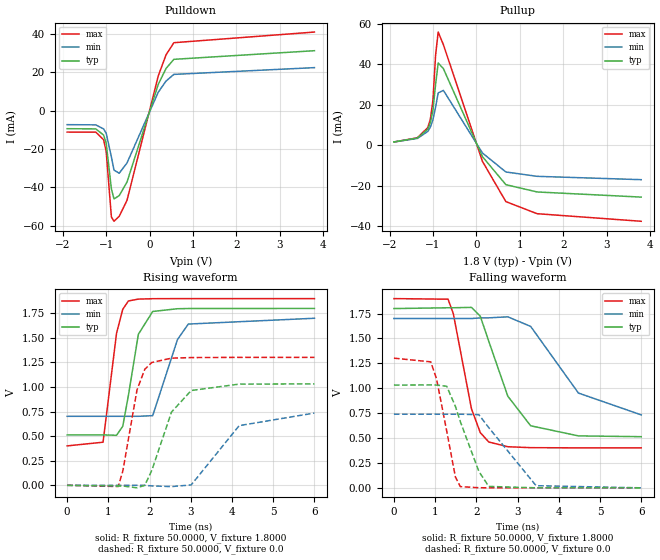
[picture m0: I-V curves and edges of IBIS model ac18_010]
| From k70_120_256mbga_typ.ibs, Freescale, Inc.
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|   Model ac18_010
[Model]  ac18_010
Model_type Output
Polarity   Non-Inverting
Enable   Active-High
Vmeas =  0.9000V
Cref =   5.0000pF
Rref =   50.0000
C_comp   2.8000pF   2.5000pF   3.3000pF
[Temperature Range]   25.0000   0.1250k   -40.0000
[Voltage Range]   1.8000V   1.7000V   1.9000V
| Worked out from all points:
|   slope of the pulldown table from 0 to 0.27 V, typ, clamps not added: 15.7 ohm
|   slope of the pullup table from 0 to 0.27 V, typ, clamps not added: 26.3 ohm
|   rising waveform, R_fixture 50.0000, V_fixture 1.8000: 20-80 % time 297ps typ, 390ps min, 244ps max; typ from 0.513 V to 1.8 V
|   rising waveform, R_fixture 50.0000, V_fixture 0.0: 20-80 % time 553ps typ, 807ps min, 342ps max; typ from 0 V to 1.03 V
|   falling waveform, R_fixture 50.0000, V_fixture 1.8000: 20-80 % time 715ps typ, 1.05ns min, 437ps max; typ from 1.8 V to 0.514 V
|   falling waveform, R_fixture 50.0000, V_fixture 0.0: 20-80 % time 535ps typ, 755ps min, 360ps max; typ from 1.03 V to 0 V
[Pulldown]
|Voltage   I(typ)   I(min)   I(max)
-1.9V     -9.45mA    -7.352mA   -11.21mA
-1.24V    -9.541mA   -7.451mA   -11.23mA
-1.06V    -12.75mA   -9.557mA   -15.18mA
-1V       -16.97mA   -11.82mA   -21.29mA
-880mV    -40.74mA   -24.13mA   -55.33mA
-820mV    -45.95mA   -31mA      -57.58mA
-700mV    -44.25mA   -32.6mA    -54.97mA
-520mV    -37.18mA   -27.26mA   -46.71mA
200mV     13.59mA    9.515mA    17.98mA
380mV     21.87mA    15.33mA    28.97mA
560mV     26.62mA    18.78mA    35.26mA
3.8V      31.1mA     22.3mA     40.8mA
[Pullup]
|Voltage   I(typ)   I(min)   I(max)
-1.9V     1.5mA      1.5mA      1.5mA
-1.36V    3.45mA     3.24mA     3.57mA
-1.12V    7.8mA      6.69mA     8.6mA
-1.06V    10.98mA    8.87mA     12.77mA
-1V       17.34mA    12.56mA    22.4mA
-940mV    29.86mA    18.76mA    44.29mA
-880mV    40.52mA    25.74mA    55.8mA
-760mV    37.72mA    26.99mA    49.56mA
140mV     -5.745mA   -3.949mA   -8.077mA
680mV     -19.58mA   -13.32mA   -27.96mA
1.4V      -23.19mA   -15.47mA   -33.93mA
3.8V      -25.73mA   -17.12mA   -37.67mA
[Ramp]
| variable   typ   min   max
dV/dt_r  0.6195/0.5526n   0.4413/0.8066n   0.7809/0.3418n
dV/dt_f  0.7719/0.7150n   0.5805/1.0484n   0.8992/0.4375n
R_load = 50.0000
[Rising Waveform]
R_fixture= 50.0000
V_fixture= 1.8000
V_fixture_min= 1.7000
V_fixture_max= 1.9000
|time   V(typ)   V(min)   V(max)
0s        513.2mV    702.3mV    401.3mV
871.4ps   513.2mV    702.3mV    438.8mV
1.199ns   509mV      702.3mV    1.548V
1.35ns    601.7mV    702.3mV    1.792V
1.487ns   916.1mV    702.3mV    1.876V
1.728ns   1.537V     702.5mV    1.895V
2.076ns   1.769V     709mV      1.899V
2.677ns   1.797V     1.483V     1.9V
2.94ns    1.799V     1.641V     1.9V
6ns       1.8V       1.7V       1.9V
[Rising Waveform]
R_fixture= 50.0000
V_fixture= 0.0
|time   V(typ)   V(min)   V(max)
0s        3.704nV    400.4nV    961.2pV
1.239ns   -7.034mV   855.3nV    -12.25mV
1.351ns   -6.76mV    491.1nV    145.3mV
1.695ns   -25.53mV   10.75uV    970.7mV
1.884ns   -346.7uV   382.5uV    1.181V
2.055ns   153.4mV    -6.023mV   1.25V
2.532ns   745.5mV    -12.79mV   1.294V
3.01ns    964.7mV    3.984mV    1.3V
4.174ns   1.03V      607.3mV    1.302V
6ns       1.032V     735.5mV    1.302V
[Falling Waveform]
R_fixture= 50.0000
V_fixture= 1.8000
V_fixture_min= 1.7000
V_fixture_max= 1.9000
|time   V(typ)   V(min)   V(max)
0s        1.8V       1.7V       1.9V
1.313ns   1.808V     1.7V       1.894V
1.441ns   1.808V     1.7V       1.748V
1.881ns   1.812V     1.7V       793.8mV
2.095ns   1.723V     1.706V     554.5mV
2.303ns   1.469V     1.707V     459.9mV
2.763ns   920.2mV    1.717V     412.8mV
3.317ns   623.2mV    1.621V     403.3mV
4.476ns   521.5mV    951.7mV    401.4mV
6ns       513.6mV    732.5mV    401.3mV
[Falling Waveform]
R_fixture= 50.0000
V_fixture= 0.0
|time   V(typ)   V(min)   V(max)
0s        1.032V     739.4mV    1.302V
892.8ps   1.033V     739.4mV    1.265V
1.034ns   1.032V     739.4mV    1.094V
1.28ns    1.02V      739.4mV    571.4mV
1.491ns   818.4mV    739.4mV    109.6mV
1.61ns    666.1mV    739.4mV    12.12mV
2.061ns   164.2mV    734.4mV    1.132mV
2.301ns   14.11mV    604.3mV    499.3uV
3.449ns   310.9uV    21.55mV    13.97uV
6ns       1.814uV    71.36uV    118.4nV
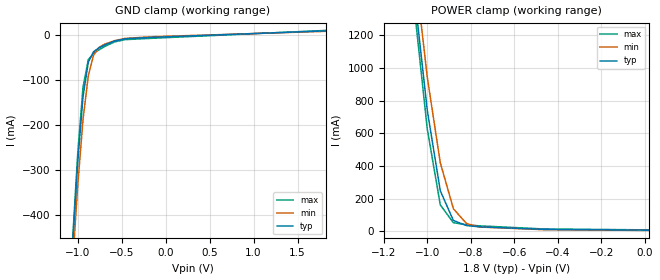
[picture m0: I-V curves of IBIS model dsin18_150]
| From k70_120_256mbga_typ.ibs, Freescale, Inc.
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|   Model dsin18_150
[Model]  dsin18_150
Model_type Input
Polarity   Non-Inverting
Enable   Active-High
Vinl =   0.6500V
Vinh =   1.1500V
C_comp   2.8000pF   2.5000pF   3.3000pF
[Temperature Range]   25.0000   0.1250k   -40.0000
[Voltage Range]   1.8000V   1.7000V   1.9000V
[GND_clamp]
|Voltage   I(typ)   I(min)   I(max)
-1.9V     -3.889A    -3.846A    -3.936A
-1.06V    -471.8mA   -515.1mA   -461.5mA
-1V       -283.2mA   -335mA     -263.8mA
-940mV    -138.2mA   -188.6mA   -116.8mA
-880mV    -61.42mA   -91.58mA   -55.71mA
-820mV    -38.02mA   -45.51mA   -41.82mA
-760mV    -29.59mA   -28.84mA   -34.03mA
-700mV    -23.58mA   -21.7mA    -27.07mA
-580mV    -14.23mA   -13.38mA   -16.04mA
-460mV    -9.258mA   -8.379mA   -11.1mA
-160mV    -6.128mA   -4.733mA   -8.206mA
1.82V     8.347mA    7.356mA    9.323mA
[POWER_clamp]
|Voltage   I(typ)   I(min)   I(max)
-1.9V     15A        14.9A      15.11A
-1.06V    1.464A     1.643A     1.375A
-1V       741.7mA    944.2mA    627.2mA
-940mV    248.2mA    419.2mA    162.4mA
-880mV    67.86mA    139.2mA    53.9mA
-820mV    36.11mA    49.11mA    40.83mA
-760mV    28.51mA    27.31mA    34.47mA
-460mV    12.75mA    10.85mA    15.2mA
20mV      8.034mA    6.463mA    9.888mA
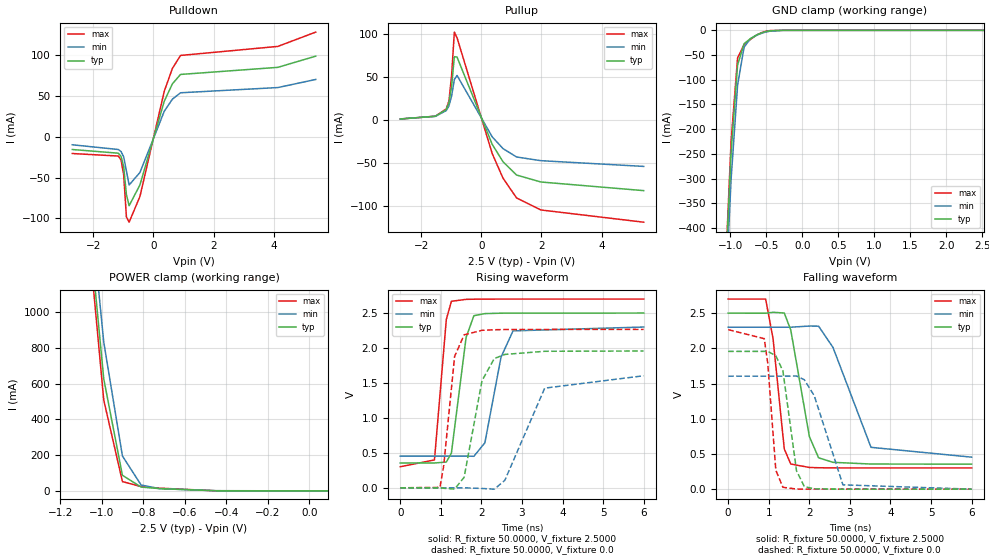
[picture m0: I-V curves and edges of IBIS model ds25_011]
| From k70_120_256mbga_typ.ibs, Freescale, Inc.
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|   Model ds25_011
[Model]  ds25_011
Model_type 3-state
Polarity   Non-Inverting
Enable   Active-High
Vmeas =  1.2500V
Cref =   5.0000pF
Rref =   50.0000
C_comp   2.8000pF   2.5000pF   3.3000pF
[Temperature Range]   25.0000   0.1250k   -40.0000
[Voltage Range]   2.5000V   2.3000V   2.7000V
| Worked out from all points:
|   slope of the pulldown table from 0 to 0.375 V, typ, clamps not added: 8.39 ohm
|   slope of the pullup table from 0 to 0.375 V, typ, clamps not added: 13 ohm
|   GND clamp passes 1 mA (typ) near -0.45 V on its own axis
|   POWER clamp passes 1 mA (typ) near -0.45 V on its own axis
|   rising waveform, R_fixture 50.0000, V_fixture 2.5000: 20-80 % time 258ps typ, 355ps min, 178ps max; typ from 0.355 V to 2.5 V
|   rising waveform, R_fixture 50.0000, V_fixture 0.0: 20-80 % time 370ps typ, 632ps min, 227ps max; typ from 0 V to 1.96 V
|   falling waveform, R_fixture 50.0000, V_fixture 2.5000: 20-80 % time 366ps typ, 605ps min, 248ps max; typ from 2.5 V to 0.355 V
|   falling waveform, R_fixture 50.0000, V_fixture 0.0: 20-80 % time 260ps typ, 438ps min, 172ps max; typ from 1.96 V to 0 V
[Pulldown]
|Voltage   I(typ)   I(min)   I(max)
-2.7V     -15.75mA   -9.975mA   -20.66mA
-1.17V    -20.25mA   -15.73mA   -23.74mA
-1.08V    -24.05mA   -18.2mA    -28.35mA
-990mV    -36.68mA   -24.84mA   -46.96mA
-900mV    -71.11mA   -42.05mA   -98.2mA
-810mV    -84.45mA   -59.11mA   -104.6mA
-450mV    -59.03mA   -43.84mA   -73.17mA
360mV     43.36mA    31.02mA    55.53mA
630mV     64.54mA    45.79mA    83.38mA
900mV     76.02mA    53.6mA     99.25mA
4.14V     84.7mA     60mA       110.3mA
5.4V      98.4mA     69.9mA     127.8mA
[Pullup]
|Voltage   I(typ)   I(min)   I(max)
-2.7V     1.5mA      1.6mA      1.5mA
-1.53V    4.72mA     4.58mA     4.76mA
-1.17V    12.5mA     11.26mA    13.19mA
-1.08V    19.99mA    16.74mA    22.33mA
-990mV    39.79mA    28.3mA     52.25mA
-900mV    73.92mA    47.3mA     102.5mA
-810mV    73.51mA    52.12mA    95.99mA
360mV     -27.92mA   -19.23mA   -38.63mA
720mV     -48.18mA   -32.89mA   -67.22mA
1.17V     -63.6mA    -42.62mA   -90.2mA
1.98V     -71.7mA    -46.92mA   -104.2mA
5.4V      -81.72mA   -53.58mA   -118.4mA
[GND_clamp]
|Voltage   I(typ)   I(min)   I(max)
-2.7V     -7.355A    -7.291A    -7.418A
-1.08V    -532.4mA   -573.9mA   -523.1mA
-990mV    -247.1mA   -301.4mA   -224.3mA
-900mV    -70.27mA   -111mA     -55.87mA
-810mV    -27.19mA   -34.32mA   -29.07mA
-720mV    -16.61mA   -16.6mA    -18.16mA
-630mV    -8.988mA   -9.498mA   -9.052mA
-540mV    -3.58mA    -4.662mA   -2.928mA
-450mV    -869.4uA   -1.668mA   -497.3uA
-270mV    -6.1uA     -54.74uA   -659.2nA
2.52V     1.073nA    13.44uA    292.2pA
[POWER_clamp]
|Voltage   I(typ)   I(min)   I(max)
-2.7V     28.59A     28.4A      28.77A
-1.08V    1.721A     1.892A     1.641A
-990mV    627.2mA    833mA      508.6mA
-900mV    87.49mA    195.4mA    52.32mA
-810mV    21.66mA    33.19mA    24.16mA
-720mV    12.85mA    12.43mA    15.46mA
-450mV    973.3uA    1.424mA    784.9uA
90mV      411.9pA    14.45nA    314.3pA
[Ramp]
| variable   typ   min   max
dV/dt_r  1.1742/0.3703n   0.9619/0.6321n   1.3594/0.2265n
dV/dt_f  1.2869/0.3658n   1.1071/0.6051n   1.4392/0.2477n
R_load = 50.0000
[Rising Waveform]
R_fixture= 50.0000
V_fixture= 2.5000
V_fixture_min= 2.3000
V_fixture_max= 2.7000
|time   V(typ)   V(min)   V(max)
0s        355.2mV    453.8mV    301.3mV
843.8ps   355.2mV    453.8mV    398.8mV
1.136ns   368.4mV    453.8mV    2.409V
1.261ns   496.7mV    453.8mV    2.668V
1.623ns   2.15V      453.8mV    2.696V
1.815ns   2.462V     450.7mV    2.698V
2.086ns   2.492V     643.4mV    2.699V
2.484ns   2.498V     1.869V     2.7V
2.78ns    2.499V     2.245V     2.7V
6ns       2.5V       2.3V       2.7V
[Rising Waveform]
R_fixture= 50.0000
V_fixture= 0.0
|time   V(typ)   V(min)   V(max)
0s        4.932nV    467.5nV    1.636nV
977.9ps   436uV      427.6nV    6.222mV
1.07ns    -6.471mV   471.7nV    309.7mV
1.34ns    -18.21mV   695.4nV    1.879V
1.575ns   150.4mV    -9.513uV   2.189V
2.015ns   1.532V     -9.474mV   2.253V
2.318ns   1.849V     -19.47mV   2.261V
2.578ns   1.908V     106.9mV    2.264V
3.561ns   1.953V     1.426V     2.266V
6ns       1.957V     1.603V     2.266V
[Falling Waveform]
R_fixture= 50.0000
V_fixture= 2.5000
V_fixture_min= 2.3000
V_fixture_max= 2.7000
|time   V(typ)   V(min)   V(max)
0s        2.5V       2.3V       2.7V
923.9ps   2.499V     2.3V       2.7V
1.107ns   2.512V     2.3V       2.137V
1.383ns   2.502V     2.3V       572.3mV
1.543ns   2.261V     2.3V       357.2mV
2.002ns   746.2mV    2.317V     308.2mV
2.229ns   445.6mV    2.315V     304.2mV
2.584ns   381mV      2.013V     302mV
3.521ns   357.1mV    594.1mV    301.3mV
6ns       355.2mV    454.8mV    301.3mV
[Falling Waveform]
R_fixture= 50.0000
V_fixture= 0.0
|time   V(typ)   V(min)   V(max)
0s        1.957V     1.605V     2.266V
890ps     1.957V     1.605V     2.138V
975.9ps   1.958V     1.605V     1.788V
1.175ns   1.894V     1.605V     268.6mV
1.35ns    1.679V     1.605V     26.64mV
1.685ns   260.3mV    1.607V     1.613mV
1.878ns   36.9mV     1.554V     775.8uV
2.122ns   4.333mV    1.328V     302.4uV
2.828ns   444.2uV    61.38mV    20.05uV
6ns       197.7nV    15.54uV    118.8nV
